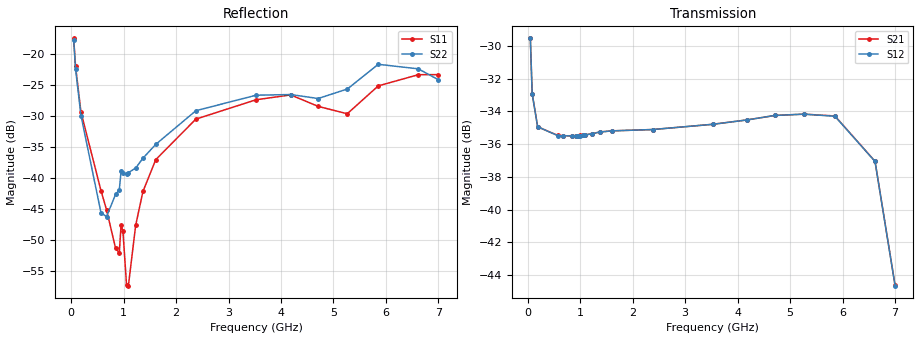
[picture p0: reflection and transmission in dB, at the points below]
! Integrated Device Technology
! Corporate Headquarters
! 6024 Silver Creek Valley Road
! San Jose, CA 95138  USA
! Phone:  1-408-284-8200
! Toll Free:  1-800-223-1366
! Webpage:  http://www.idt.com/
! Timing and RF Division
! 515 Groton Road, Suite 102
! Westford, MA 01886-6024
! Device:  F2258
! Description: Voltage Variable RF Attenuator
! Frequency:  50.0 -  6000.00 MHz
! Package:  3x3 mm Thin QFN Plastic Package: 16 pin
! Ports:  2 RF, 2 DC
!  Pin  1  = NC
!  Pin  2  = NC
!  Pin  3  = RF2  = Port 2
!  Pin  4  = GND
!  Pin  5  = Vdd
!  Pin  6  = NC
!  Pin  7  = VCTRL
!  Pin  8  = NC
!  Pin  9  = GND
!  Pin 10  = RF1  = Port 1
!  Pin 11  = NC
!  Pin 12  = NC
!  Pin 13  = NC
!  Pin 14  = NC
!  Pin 15  = NC
!  Pin 16  = NC
! Vcntrl:  2.410 Volts
! Vdd:  +3.300 Volts
! Current:  1.146 mA
! Data:  The device was measured on a the F2258 evaluation board which has
!  individual transmission lines to the RF pins.  Data was collected
!  using a calibrated network analyzer.  The evaluation board was
!  de-embedded using a TRL calibration technique.
!  The reference plane is the edge of the package pin.
! Misc:  SN 10
!  Action Tracker AT0285
! Date Measured:  2014-12-10
! Date:  2016-01-13  MJV
! Note:
!  Integrated Device Technology supplies this data as a sample of measured
!  data at the package pin for this product.  Your particular data for this
!  product may vary.
!  Data was taken at 25 degrees C.
!  Integrated Device Technology reserves the right to change this data at anytime.
!Freq_(GHz)  S11M_(dB)  S11P_(deg)  S21M_(dB)  S21P_(deg)  S12M_(dB)  S12P_(deg)  S22M_(dB)  S22P_(deg)
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# GHz S dB R 50
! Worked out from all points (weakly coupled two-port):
!   201 points, 50 MHz to 7 GHz, reference 50 ohm
!   highest |S21| = -29.54 dB at 50 MHz (marker M1); lowest = -44.6 dB at 7 GHz (marker M2)
!   lowest |S11| = -57.3 dB at 1.093 GHz (marker M3), VSWR 1.00, Z = 49.9 + j0.113 ohm
!   |S11| at or under -10 dB: start of sweep to end of sweep
!   |S22| runs from -46.2 to -17.8 dB; largest |S21 - S12| = 6.3e-05
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0.05  -17.55 -111.0  -29.54 -68.7  -29.54 -68.7  -17.77 -111.7
0.08475  -21.98 -107.4  -32.92 -48.9  -32.92 -48.9  -22.40 -108.5
0.189  -29.41 -109.5  -34.94 -24.8  -34.94 -24.8  -29.96 -112.4
0.57125  -42.06 -125.2  -35.47 -10.4  -35.48 -10.4  -45.62 -170.4
0.6755  -45.09 -132.5  -35.49 -9.4  -35.49 -9.4  -46.20 154.2
0.84925  -51.33 -175.7  -35.49 -8.5  -35.50 -8.5  -42.60 128.0
0.91875  -52.06 150.5  -35.49 -8.3  -35.48 -8.3  -41.94 124.6
0.9535  -47.55 -163.4  -35.50 -8.2  -35.50 -8.2  -38.88 127.7
0.98825  -48.50 -174.9  -35.47 -8.1  -35.48 -8.1  -39.21 125.8
1.05775  -57.26 153.0  -35.46 -7.9  -35.46 -7.9  -39.31 112.5
1.0925  -57.31 124.2  -35.44 -7.8  -35.44 -7.8  -39.14 108.5
1.2315  -47.59 46.2  -35.36 -7.8  -35.37 -7.9  -38.40 87.0
1.3705  -42.14 37.4  -35.26 -8.3  -35.26 -8.2  -36.81 73.2
1.61375  -37.05 32.9  -35.19 -9.5  -35.19 -9.5  -34.59 58.1
2.37825  -30.53 48.0  -35.11 -13.1  -35.11 -13.1  -29.18 46.0
3.525  -27.42 91.6  -34.79 -19.4  -34.79 -19.4  -26.69 69.1
4.18525  -26.64 105.0  -34.52 -23.9  -34.52 -24.0  -26.58 75.5
4.7065  -28.48 95.7  -34.25 -28.5  -34.25 -28.5  -27.22 60.2
5.2625  -29.67 54.3  -34.17 -34.7  -34.17 -34.7  -25.70 23.0
5.85325  -25.19 29.9  -34.28 -45.4  -34.30 -45.3  -21.72 -1.4
6.61775  -23.39 49.7  -37.05 -68.6  -37.06 -68.6  -22.45 -43.4
7  -23.38 84.5  -44.63 -61.3  -44.65 -61.0  -24.21 -130.2
